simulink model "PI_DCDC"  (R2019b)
settings: Solver=ode4  StartTime=0.0  StopTime=0.25  FixedStep=2e-5  RelTol=1e-3  EnableMultiTasking=on
libraries: SCIDEAM_BLOCKS_100 x2

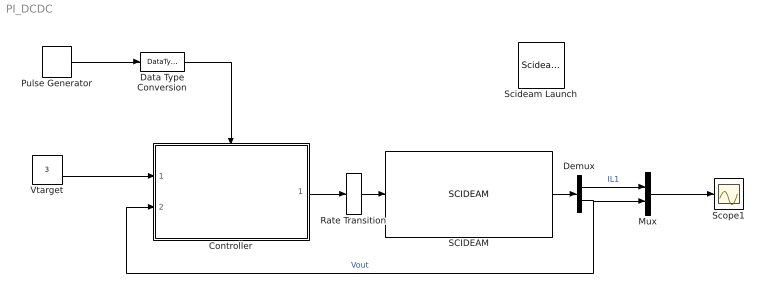
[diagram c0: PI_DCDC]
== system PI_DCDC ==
  Controller : Subsystem
  Data Type Conversion : DataTypeConversion  OutDataTypeStr=boolean
  Demux : Demux  Outputs=2
  Mux : Mux  Inputs=2
  Pulse Generator : DiscretePulseGenerator  PulseType=Time based  Period=0.15  PulseWidth=75
  Rate Transition : RateTransition  OutPortSampleTime=2e-5
  SCIDEAM : SCIDEAM_BLOCKS_100/SCIDEAM  ScalCliPath=Scal.Cli.exe  CvtFilePath=PI_dcdc.cvt2  SimulationMode=Transient  WaveformStartTime=0  FrequencyResponseAnalysisStartTime=0  VasSymbols=<empty>  FromSignatures=<empty>  ToSignatures=<empty>  PhaseFold=on  InputWidth=1  OutputWidth=2
  Scideam Launch : SCIDEAM_BLOCKS_100/Scideam Launch
  Scope1 : Scope
  Vtarget : Constant  Value=3
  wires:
  Rate Transition/1 -> SCIDEAM/1
  SCIDEAM/1 -> Demux/1
  Mux/1 -> Scope1/1
  Demux/1 -> Mux/1  "IL1"
  Demux/2 -> Controller/2(Vout), Mux/2  "Vout"
  Vtarget/1 -> Controller/1(Vtarget)
  Controller/1(Duty) -> Rate Transition/1
  Pulse Generator/1 -> Data Type Conversion/1
  Data Type Conversion/1 -> Controller/Enable

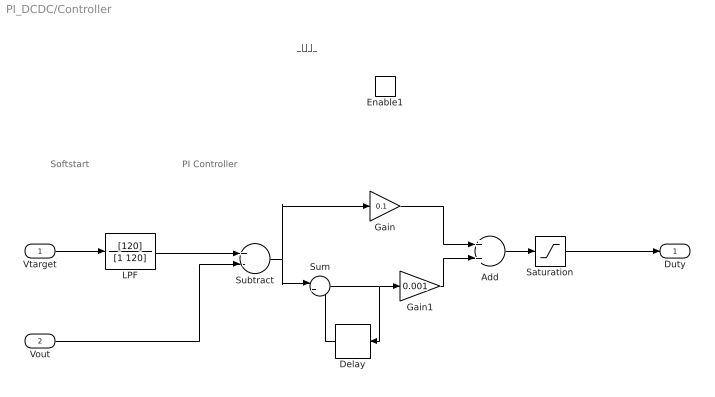
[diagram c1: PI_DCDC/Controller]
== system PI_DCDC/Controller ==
  note: オンオフ
  note: PI Controller
  note: Softstart
  Vtarget : Inport
  Vout : Inport  Port=2
  Enable1 : EnablePort  StatesWhenEnabling=reset
  Add : Sum
  Delay : Delay  DelayLength=1  InitialCondition=0
  Gain : Gain  Gain=0.1
  Gain1 : Gain  Gain=0.001
  LPF : TransferFcn  Numerator=[120]  Denominator=[1 120]
  Saturation : Saturate  UpperLimit=1  LowerLimit=0
  Subtract : Sum  Inputs=+-
  Sum : Sum  Inputs=|++
  Duty : Outport  OutputWhenDisabled=reset  InitialOutput=[0]
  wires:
  Sum/1 -> Delay/1, Gain1/1
  Subtract/1 -> Gain/1, Sum/1
  Gain1/1 -> Add/2
  Delay/1 -> Sum/2
  Vtarget/1 -> LPF/1
  Vout/1 -> Subtract/2
  Gain/1 -> Add/1
  Add/1 -> Saturation/1
  LPF/1 -> Subtract/1
  Saturation/1 -> Duty/1
